VERSION 5.7 ;
BUSBITCHARS "[]" ;
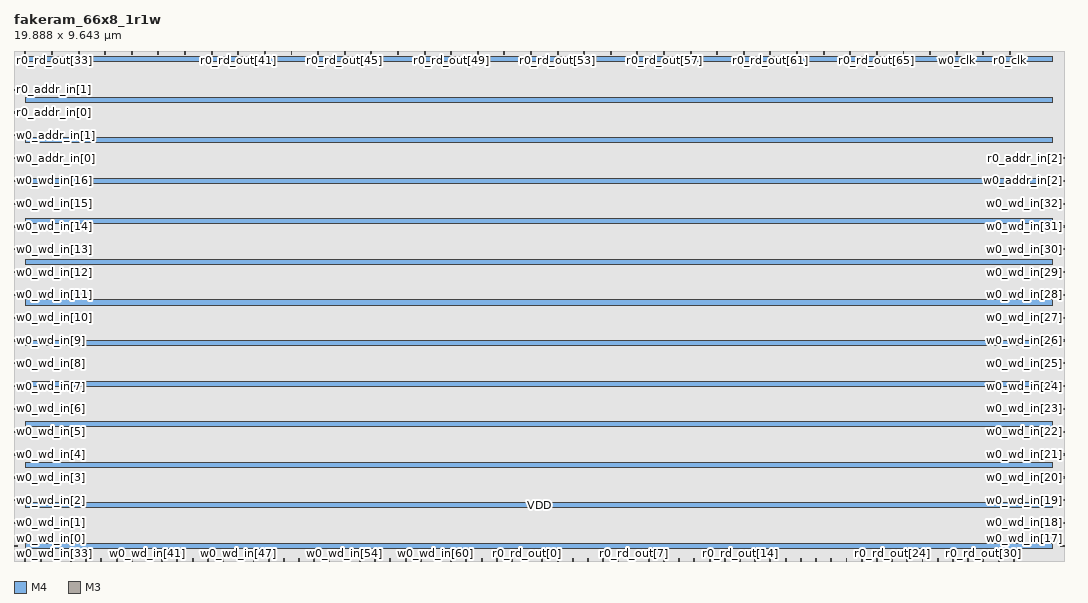
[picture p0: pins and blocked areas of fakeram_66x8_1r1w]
MACRO fakeram_66x8_1r1w
  FOREIGN fakeram_66x8_1r1w 0 0 ;
  SYMMETRY X Y R90 ;
  SIZE 19.888 BY 9.643 ;
  CLASS BLOCK ;
  PIN w0_wd_in[0]
    DIRECTION INPUT ;
    USE SIGNAL ;
    SHAPE ABUTMENT ;
    PORT
      LAYER M4 ;
      RECT 0.000 0.276 0.072 0.300 ;
    END
  END w0_wd_in[0]
  PIN w0_wd_in[1]
    DIRECTION INPUT ;
    USE SIGNAL ;
    SHAPE ABUTMENT ;
    PORT
      LAYER M4 ;
      RECT 0.000 0.708 0.072 0.732 ;
    END
  END w0_wd_in[1]
  PIN w0_wd_in[2]
    DIRECTION INPUT ;
    USE SIGNAL ;
    SHAPE ABUTMENT ;
    PORT
      LAYER M4 ;
      RECT 0.000 1.140 0.072 1.164 ;
    END
  END w0_wd_in[2]
  PIN w0_wd_in[3]
    DIRECTION INPUT ;
    USE SIGNAL ;
    SHAPE ABUTMENT ;
    PORT
      LAYER M4 ;
      RECT 0.000 1.572 0.072 1.596 ;
    END
  END w0_wd_in[3]
  PIN w0_wd_in[4]
    DIRECTION INPUT ;
    USE SIGNAL ;
    SHAPE ABUTMENT ;
    PORT
      LAYER M4 ;
      RECT 0.000 2.004 0.072 2.028 ;
    END
  END w0_wd_in[4]
  PIN w0_wd_in[5]
    DIRECTION INPUT ;
    USE SIGNAL ;
    SHAPE ABUTMENT ;
    PORT
      LAYER M4 ;
      RECT 0.000 2.436 0.072 2.460 ;
    END
  END w0_wd_in[5]
  PIN w0_wd_in[6]
    DIRECTION INPUT ;
    USE SIGNAL ;
    SHAPE ABUTMENT ;
    PORT
      LAYER M4 ;
      RECT 0.000 2.868 0.072 2.892 ;
    END
  END w0_wd_in[6]
  PIN w0_wd_in[7]
    DIRECTION INPUT ;
    USE SIGNAL ;
    SHAPE ABUTMENT ;
    PORT
      LAYER M4 ;
      RECT 0.000 3.300 0.072 3.324 ;
    END
  END w0_wd_in[7]
  PIN w0_wd_in[8]
    DIRECTION INPUT ;
    USE SIGNAL ;
    SHAPE ABUTMENT ;
    PORT
      LAYER M4 ;
      RECT 0.000 3.732 0.072 3.756 ;
    END
  END w0_wd_in[8]
  PIN w0_wd_in[9]
    DIRECTION INPUT ;
    USE SIGNAL ;
    SHAPE ABUTMENT ;
    PORT
      LAYER M4 ;
      RECT 0.000 4.164 0.072 4.188 ;
    END
  END w0_wd_in[9]
  PIN w0_wd_in[10]
    DIRECTION INPUT ;
    USE SIGNAL ;
    SHAPE ABUTMENT ;
    PORT
      LAYER M4 ;
      RECT 0.000 4.596 0.072 4.620 ;
    END
  END w0_wd_in[10]
  PIN w0_wd_in[11]
    DIRECTION INPUT ;
    USE SIGNAL ;
    SHAPE ABUTMENT ;
    PORT
      LAYER M4 ;
      RECT 0.000 5.028 0.072 5.052 ;
    END
  END w0_wd_in[11]
  PIN w0_wd_in[12]
    DIRECTION INPUT ;
    USE SIGNAL ;
    SHAPE ABUTMENT ;
    PORT
      LAYER M4 ;
      RECT 0.000 5.460 0.072 5.484 ;
    END
  END w0_wd_in[12]
  PIN w0_wd_in[13]
    DIRECTION INPUT ;
    USE SIGNAL ;
    SHAPE ABUTMENT ;
    PORT
      LAYER M4 ;
      RECT 0.000 5.892 0.072 5.916 ;
    END
  END w0_wd_in[13]
  PIN w0_wd_in[14]
    DIRECTION INPUT ;
    USE SIGNAL ;
    SHAPE ABUTMENT ;
    PORT
      LAYER M4 ;
      RECT 0.000 6.324 0.072 6.348 ;
    END
  END w0_wd_in[14]
  PIN w0_wd_in[15]
    DIRECTION INPUT ;
    USE SIGNAL ;
    SHAPE ABUTMENT ;
    PORT
      LAYER M4 ;
      RECT 0.000 6.756 0.072 6.780 ;
    END
  END w0_wd_in[15]
  PIN w0_wd_in[16]
    DIRECTION INPUT ;
    USE SIGNAL ;
    SHAPE ABUTMENT ;
    PORT
      LAYER M4 ;
      RECT 0.000 7.188 0.072 7.212 ;
    END
  END w0_wd_in[16]
  PIN w0_wd_in[17]
    DIRECTION INPUT ;
    USE SIGNAL ;
    SHAPE ABUTMENT ;
    PORT
      LAYER M4 ;
      RECT 19.816 0.276 19.888 0.300 ;
    END
  END w0_wd_in[17]
  PIN w0_wd_in[18]
    DIRECTION INPUT ;
    USE SIGNAL ;
    SHAPE ABUTMENT ;
    PORT
      LAYER M4 ;
      RECT 19.816 0.708 19.888 0.732 ;
    END
  END w0_wd_in[18]
  PIN w0_wd_in[19]
    DIRECTION INPUT ;
    USE SIGNAL ;
    SHAPE ABUTMENT ;
    PORT
      LAYER M4 ;
      RECT 19.816 1.140 19.888 1.164 ;
    END
  END w0_wd_in[19]
  PIN w0_wd_in[20]
    DIRECTION INPUT ;
    USE SIGNAL ;
    SHAPE ABUTMENT ;
    PORT
      LAYER M4 ;
      RECT 19.816 1.572 19.888 1.596 ;
    END
  END w0_wd_in[20]
  PIN w0_wd_in[21]
    DIRECTION INPUT ;
    USE SIGNAL ;
    SHAPE ABUTMENT ;
    PORT
      LAYER M4 ;
      RECT 19.816 2.004 19.888 2.028 ;
    END
  END w0_wd_in[21]
  PIN w0_wd_in[22]
    DIRECTION INPUT ;
    USE SIGNAL ;
    SHAPE ABUTMENT ;
    PORT
      LAYER M4 ;
      RECT 19.816 2.436 19.888 2.460 ;
    END
  END w0_wd_in[22]
  PIN w0_wd_in[23]
    DIRECTION INPUT ;
    USE SIGNAL ;
    SHAPE ABUTMENT ;
    PORT
      LAYER M4 ;
      RECT 19.816 2.868 19.888 2.892 ;
    END
  END w0_wd_in[23]
  PIN w0_wd_in[24]
    DIRECTION INPUT ;
    USE SIGNAL ;
    SHAPE ABUTMENT ;
    PORT
      LAYER M4 ;
      RECT 19.816 3.300 19.888 3.324 ;
    END
  END w0_wd_in[24]
  PIN w0_wd_in[25]
    DIRECTION INPUT ;
    USE SIGNAL ;
    SHAPE ABUTMENT ;
    PORT
      LAYER M4 ;
      RECT 19.816 3.732 19.888 3.756 ;
    END
  END w0_wd_in[25]
  PIN w0_wd_in[26]
    DIRECTION INPUT ;
    USE SIGNAL ;
    SHAPE ABUTMENT ;
    PORT
      LAYER M4 ;
      RECT 19.816 4.164 19.888 4.188 ;
    END
  END w0_wd_in[26]
  PIN w0_wd_in[27]
    DIRECTION INPUT ;
    USE SIGNAL ;
    SHAPE ABUTMENT ;
    PORT
      LAYER M4 ;
      RECT 19.816 4.596 19.888 4.620 ;
    END
  END w0_wd_in[27]
  PIN w0_wd_in[28]
    DIRECTION INPUT ;
    USE SIGNAL ;
    SHAPE ABUTMENT ;
    PORT
      LAYER M4 ;
      RECT 19.816 5.028 19.888 5.052 ;
    END
  END w0_wd_in[28]
  PIN w0_wd_in[29]
    DIRECTION INPUT ;
    USE SIGNAL ;
    SHAPE ABUTMENT ;
    PORT
      LAYER M4 ;
      RECT 19.816 5.460 19.888 5.484 ;
    END
  END w0_wd_in[29]
  PIN w0_wd_in[30]
    DIRECTION INPUT ;
    USE SIGNAL ;
    SHAPE ABUTMENT ;
    PORT
      LAYER M4 ;
      RECT 19.816 5.892 19.888 5.916 ;
    END
  END w0_wd_in[30]
  PIN w0_wd_in[31]
    DIRECTION INPUT ;
    USE SIGNAL ;
    SHAPE ABUTMENT ;
    PORT
      LAYER M4 ;
      RECT 19.816 6.324 19.888 6.348 ;
    END
  END w0_wd_in[31]
  PIN w0_wd_in[32]
    DIRECTION INPUT ;
    USE SIGNAL ;
    SHAPE ABUTMENT ;
    PORT
      LAYER M4 ;
      RECT 19.816 6.756 19.888 6.780 ;
    END
  END w0_wd_in[32]
  PIN w0_wd_in[33]
    DIRECTION OUTPUT ;
    USE SIGNAL ;
    SHAPE ABUTMENT ;
    PORT
      LAYER M3 ;
      RECT 0.207 0.000 0.225 0.054 ;
    END
  END w0_wd_in[33]
  PIN w0_wd_in[34]
    DIRECTION OUTPUT ;
    USE SIGNAL ;
    SHAPE ABUTMENT ;
    PORT
      LAYER M3 ;
      RECT 0.495 0.000 0.513 0.054 ;
    END
  END w0_wd_in[34]
  PIN w0_wd_in[35]
    DIRECTION OUTPUT ;
    USE SIGNAL ;
    SHAPE ABUTMENT ;
    PORT
      LAYER M3 ;
      RECT 0.783 0.000 0.801 0.054 ;
    END
  END w0_wd_in[35]
  PIN w0_wd_in[36]
    DIRECTION OUTPUT ;
    USE SIGNAL ;
    SHAPE ABUTMENT ;
    PORT
      LAYER M3 ;
      RECT 1.071 0.000 1.089 0.054 ;
    END
  END w0_wd_in[36]
  PIN w0_wd_in[37]
    DIRECTION OUTPUT ;
    USE SIGNAL ;
    SHAPE ABUTMENT ;
    PORT
      LAYER M3 ;
      RECT 1.359 0.000 1.377 0.054 ;
    END
  END w0_wd_in[37]
  PIN w0_wd_in[38]
    DIRECTION OUTPUT ;
    USE SIGNAL ;
    SHAPE ABUTMENT ;
    PORT
      LAYER M3 ;
      RECT 1.647 0.000 1.665 0.054 ;
    END
  END w0_wd_in[38]
  PIN w0_wd_in[39]
    DIRECTION OUTPUT ;
    USE SIGNAL ;
    SHAPE ABUTMENT ;
    PORT
      LAYER M3 ;
      RECT 1.935 0.000 1.953 0.054 ;
    END
  END w0_wd_in[39]
  PIN w0_wd_in[40]
    DIRECTION OUTPUT ;
    USE SIGNAL ;
    SHAPE ABUTMENT ;
    PORT
      LAYER M3 ;
      RECT 2.223 0.000 2.241 0.054 ;
    END
  END w0_wd_in[40]
  PIN w0_wd_in[41]
    DIRECTION OUTPUT ;
    USE SIGNAL ;
    SHAPE ABUTMENT ;
    PORT
      LAYER M3 ;
      RECT 2.511 0.000 2.529 0.054 ;
    END
  END w0_wd_in[41]
  PIN w0_wd_in[42]
    DIRECTION OUTPUT ;
    USE SIGNAL ;
    SHAPE ABUTMENT ;
    PORT
      LAYER M3 ;
      RECT 2.799 0.000 2.817 0.054 ;
    END
  END w0_wd_in[42]
  PIN w0_wd_in[43]
    DIRECTION OUTPUT ;
    USE SIGNAL ;
    SHAPE ABUTMENT ;
    PORT
      LAYER M3 ;
      RECT 3.087 0.000 3.105 0.054 ;
    END
  END w0_wd_in[43]
  PIN w0_wd_in[44]
    DIRECTION OUTPUT ;
    USE SIGNAL ;
    SHAPE ABUTMENT ;
    PORT
      LAYER M3 ;
      RECT 3.375 0.000 3.393 0.054 ;
    END
  END w0_wd_in[44]
  PIN w0_wd_in[45]
    DIRECTION OUTPUT ;
    USE SIGNAL ;
    SHAPE ABUTMENT ;
    PORT
      LAYER M3 ;
      RECT 3.663 0.000 3.681 0.054 ;
    END
  END w0_wd_in[45]
  PIN w0_wd_in[46]
    DIRECTION OUTPUT ;
    USE SIGNAL ;
    SHAPE ABUTMENT ;
    PORT
      LAYER M3 ;
      RECT 3.951 0.000 3.969 0.054 ;
    END
  END w0_wd_in[46]
  PIN w0_wd_in[47]
    DIRECTION OUTPUT ;
    USE SIGNAL ;
    SHAPE ABUTMENT ;
    PORT
      LAYER M3 ;
      RECT 4.239 0.000 4.257 0.054 ;
    END
  END w0_wd_in[47]
  PIN w0_wd_in[48]
    DIRECTION OUTPUT ;
    USE SIGNAL ;
    SHAPE ABUTMENT ;
    PORT
      LAYER M3 ;
      RECT 4.527 0.000 4.545 0.054 ;
    END
  END w0_wd_in[48]
  PIN w0_wd_in[49]
    DIRECTION OUTPUT ;
    USE SIGNAL ;
    SHAPE ABUTMENT ;
    PORT
      LAYER M3 ;
      RECT 4.815 0.000 4.833 0.054 ;
    END
  END w0_wd_in[49]
  PIN w0_wd_in[50]
    DIRECTION OUTPUT ;
    USE SIGNAL ;
    SHAPE ABUTMENT ;
    PORT
      LAYER M3 ;
      RECT 5.103 0.000 5.121 0.054 ;
    END
  END w0_wd_in[50]
  PIN w0_wd_in[51]
    DIRECTION OUTPUT ;
    USE SIGNAL ;
    SHAPE ABUTMENT ;
    PORT
      LAYER M3 ;
      RECT 5.391 0.000 5.409 0.054 ;
    END
  END w0_wd_in[51]
  PIN w0_wd_in[52]
    DIRECTION OUTPUT ;
    USE SIGNAL ;
    SHAPE ABUTMENT ;
    PORT
      LAYER M3 ;
      RECT 5.679 0.000 5.697 0.054 ;
    END
  END w0_wd_in[52]
  PIN w0_wd_in[53]
    DIRECTION OUTPUT ;
    USE SIGNAL ;
    SHAPE ABUTMENT ;
    PORT
      LAYER M3 ;
      RECT 5.967 0.000 5.985 0.054 ;
    END
  END w0_wd_in[53]
  PIN w0_wd_in[54]
    DIRECTION OUTPUT ;
    USE SIGNAL ;
    SHAPE ABUTMENT ;
    PORT
      LAYER M3 ;
      RECT 6.255 0.000 6.273 0.054 ;
    END
  END w0_wd_in[54]
  PIN w0_wd_in[55]
    DIRECTION OUTPUT ;
    USE SIGNAL ;
    SHAPE ABUTMENT ;
    PORT
      LAYER M3 ;
      RECT 6.543 0.000 6.561 0.054 ;
    END
  END w0_wd_in[55]
  PIN w0_wd_in[56]
    DIRECTION OUTPUT ;
    USE SIGNAL ;
    SHAPE ABUTMENT ;
    PORT
      LAYER M3 ;
      RECT 6.831 0.000 6.849 0.054 ;
    END
  END w0_wd_in[56]
  PIN w0_wd_in[57]
    DIRECTION OUTPUT ;
    USE SIGNAL ;
    SHAPE ABUTMENT ;
    PORT
      LAYER M3 ;
      RECT 7.119 0.000 7.137 0.054 ;
    END
  END w0_wd_in[57]
  PIN w0_wd_in[58]
    DIRECTION OUTPUT ;
    USE SIGNAL ;
    SHAPE ABUTMENT ;
    PORT
      LAYER M3 ;
      RECT 7.407 0.000 7.425 0.054 ;
    END
  END w0_wd_in[58]
  PIN w0_wd_in[59]
    DIRECTION OUTPUT ;
    USE SIGNAL ;
    SHAPE ABUTMENT ;
    PORT
      LAYER M3 ;
      RECT 7.695 0.000 7.713 0.054 ;
    END
  END w0_wd_in[59]
  PIN w0_wd_in[60]
    DIRECTION OUTPUT ;
    USE SIGNAL ;
    SHAPE ABUTMENT ;
    PORT
      LAYER M3 ;
      RECT 7.983 0.000 8.001 0.054 ;
    END
  END w0_wd_in[60]
  PIN w0_wd_in[61]
    DIRECTION OUTPUT ;
    USE SIGNAL ;
    SHAPE ABUTMENT ;
    PORT
      LAYER M3 ;
      RECT 8.271 0.000 8.289 0.054 ;
    END
  END w0_wd_in[61]
  PIN w0_wd_in[62]
    DIRECTION OUTPUT ;
    USE SIGNAL ;
    SHAPE ABUTMENT ;
    PORT
      LAYER M3 ;
      RECT 8.559 0.000 8.577 0.054 ;
    END
  END w0_wd_in[62]
  PIN w0_wd_in[63]
    DIRECTION OUTPUT ;
    USE SIGNAL ;
    SHAPE ABUTMENT ;
    PORT
      LAYER M3 ;
      RECT 8.847 0.000 8.865 0.054 ;
    END
  END w0_wd_in[63]
  PIN w0_wd_in[64]
    DIRECTION OUTPUT ;
    USE SIGNAL ;
    SHAPE ABUTMENT ;
    PORT
      LAYER M3 ;
      RECT 9.135 0.000 9.153 0.054 ;
    END
  END w0_wd_in[64]
  PIN w0_wd_in[65]
    DIRECTION OUTPUT ;
    USE SIGNAL ;
    SHAPE ABUTMENT ;
    PORT
      LAYER M3 ;
      RECT 9.423 0.000 9.441 0.054 ;
    END
  END w0_wd_in[65]
  PIN r0_rd_out[0]
    DIRECTION OUTPUT ;
    USE SIGNAL ;
    SHAPE ABUTMENT ;
    PORT
      LAYER M3 ;
      RECT 9.711 0.000 9.729 0.054 ;
    END
  END r0_rd_out[0]
  PIN r0_rd_out[1]
    DIRECTION OUTPUT ;
    USE SIGNAL ;
    SHAPE ABUTMENT ;
    PORT
      LAYER M3 ;
      RECT 9.999 0.000 10.017 0.054 ;
    END
  END r0_rd_out[1]
  PIN r0_rd_out[2]
    DIRECTION OUTPUT ;
    USE SIGNAL ;
    SHAPE ABUTMENT ;
    PORT
      LAYER M3 ;
      RECT 10.287 0.000 10.305 0.054 ;
    END
  END r0_rd_out[2]
  PIN r0_rd_out[3]
    DIRECTION OUTPUT ;
    USE SIGNAL ;
    SHAPE ABUTMENT ;
    PORT
      LAYER M3 ;
      RECT 10.575 0.000 10.593 0.054 ;
    END
  END r0_rd_out[3]
  PIN r0_rd_out[4]
    DIRECTION OUTPUT ;
    USE SIGNAL ;
    SHAPE ABUTMENT ;
    PORT
      LAYER M3 ;
      RECT 10.863 0.000 10.881 0.054 ;
    END
  END r0_rd_out[4]
  PIN r0_rd_out[5]
    DIRECTION OUTPUT ;
    USE SIGNAL ;
    SHAPE ABUTMENT ;
    PORT
      LAYER M3 ;
      RECT 11.151 0.000 11.169 0.054 ;
    END
  END r0_rd_out[5]
  PIN r0_rd_out[6]
    DIRECTION OUTPUT ;
    USE SIGNAL ;
    SHAPE ABUTMENT ;
    PORT
      LAYER M3 ;
      RECT 11.439 0.000 11.457 0.054 ;
    END
  END r0_rd_out[6]
  PIN r0_rd_out[7]
    DIRECTION OUTPUT ;
    USE SIGNAL ;
    SHAPE ABUTMENT ;
    PORT
      LAYER M3 ;
      RECT 11.727 0.000 11.745 0.054 ;
    END
  END r0_rd_out[7]
  PIN r0_rd_out[8]
    DIRECTION OUTPUT ;
    USE SIGNAL ;
    SHAPE ABUTMENT ;
    PORT
      LAYER M3 ;
      RECT 12.015 0.000 12.033 0.054 ;
    END
  END r0_rd_out[8]
  PIN r0_rd_out[9]
    DIRECTION OUTPUT ;
    USE SIGNAL ;
    SHAPE ABUTMENT ;
    PORT
      LAYER M3 ;
      RECT 12.303 0.000 12.321 0.054 ;
    END
  END r0_rd_out[9]
  PIN r0_rd_out[10]
    DIRECTION OUTPUT ;
    USE SIGNAL ;
    SHAPE ABUTMENT ;
    PORT
      LAYER M3 ;
      RECT 12.591 0.000 12.609 0.054 ;
    END
  END r0_rd_out[10]
  PIN r0_rd_out[11]
    DIRECTION OUTPUT ;
    USE SIGNAL ;
    SHAPE ABUTMENT ;
    PORT
      LAYER M3 ;
      RECT 12.879 0.000 12.897 0.054 ;
    END
  END r0_rd_out[11]
  PIN r0_rd_out[12]
    DIRECTION OUTPUT ;
    USE SIGNAL ;
    SHAPE ABUTMENT ;
    PORT
      LAYER M3 ;
      RECT 13.167 0.000 13.185 0.054 ;
    END
  END r0_rd_out[12]
  PIN r0_rd_out[13]
    DIRECTION OUTPUT ;
    USE SIGNAL ;
    SHAPE ABUTMENT ;
    PORT
      LAYER M3 ;
      RECT 13.455 0.000 13.473 0.054 ;
    END
  END r0_rd_out[13]
  PIN r0_rd_out[14]
    DIRECTION OUTPUT ;
    USE SIGNAL ;
    SHAPE ABUTMENT ;
    PORT
      LAYER M3 ;
      RECT 13.743 0.000 13.761 0.054 ;
    END
  END r0_rd_out[14]
  PIN r0_rd_out[15]
    DIRECTION OUTPUT ;
    USE SIGNAL ;
    SHAPE ABUTMENT ;
    PORT
      LAYER M3 ;
      RECT 14.031 0.000 14.049 0.054 ;
    END
  END r0_rd_out[15]
  PIN r0_rd_out[16]
    DIRECTION OUTPUT ;
    USE SIGNAL ;
    SHAPE ABUTMENT ;
    PORT
      LAYER M3 ;
      RECT 14.319 0.000 14.337 0.054 ;
    END
  END r0_rd_out[16]
  PIN r0_rd_out[17]
    DIRECTION OUTPUT ;
    USE SIGNAL ;
    SHAPE ABUTMENT ;
    PORT
      LAYER M3 ;
      RECT 14.607 0.000 14.625 0.054 ;
    END
  END r0_rd_out[17]
  PIN r0_rd_out[18]
    DIRECTION OUTPUT ;
    USE SIGNAL ;
    SHAPE ABUTMENT ;
    PORT
      LAYER M3 ;
      RECT 14.895 0.000 14.913 0.054 ;
    END
  END r0_rd_out[18]
  PIN r0_rd_out[19]
    DIRECTION OUTPUT ;
    USE SIGNAL ;
    SHAPE ABUTMENT ;
    PORT
      LAYER M3 ;
      RECT 15.183 0.000 15.201 0.054 ;
    END
  END r0_rd_out[19]
  PIN r0_rd_out[20]
    DIRECTION OUTPUT ;
    USE SIGNAL ;
    SHAPE ABUTMENT ;
    PORT
      LAYER M3 ;
      RECT 15.471 0.000 15.489 0.054 ;
    END
  END r0_rd_out[20]
  PIN r0_rd_out[21]
    DIRECTION OUTPUT ;
    USE SIGNAL ;
    SHAPE ABUTMENT ;
    PORT
      LAYER M3 ;
      RECT 15.759 0.000 15.777 0.054 ;
    END
  END r0_rd_out[21]
  PIN r0_rd_out[22]
    DIRECTION OUTPUT ;
    USE SIGNAL ;
    SHAPE ABUTMENT ;
    PORT
      LAYER M3 ;
      RECT 16.047 0.000 16.065 0.054 ;
    END
  END r0_rd_out[22]
  PIN r0_rd_out[23]
    DIRECTION OUTPUT ;
    USE SIGNAL ;
    SHAPE ABUTMENT ;
    PORT
      LAYER M3 ;
      RECT 16.335 0.000 16.353 0.054 ;
    END
  END r0_rd_out[23]
  PIN r0_rd_out[24]
    DIRECTION OUTPUT ;
    USE SIGNAL ;
    SHAPE ABUTMENT ;
    PORT
      LAYER M3 ;
      RECT 16.623 0.000 16.641 0.054 ;
    END
  END r0_rd_out[24]
  PIN r0_rd_out[25]
    DIRECTION OUTPUT ;
    USE SIGNAL ;
    SHAPE ABUTMENT ;
    PORT
      LAYER M3 ;
      RECT 16.911 0.000 16.929 0.054 ;
    END
  END r0_rd_out[25]
  PIN r0_rd_out[26]
    DIRECTION OUTPUT ;
    USE SIGNAL ;
    SHAPE ABUTMENT ;
    PORT
      LAYER M3 ;
      RECT 17.199 0.000 17.217 0.054 ;
    END
  END r0_rd_out[26]
  PIN r0_rd_out[27]
    DIRECTION OUTPUT ;
    USE SIGNAL ;
    SHAPE ABUTMENT ;
    PORT
      LAYER M3 ;
      RECT 17.487 0.000 17.505 0.054 ;
    END
  END r0_rd_out[27]
  PIN r0_rd_out[28]
    DIRECTION OUTPUT ;
    USE SIGNAL ;
    SHAPE ABUTMENT ;
    PORT
      LAYER M3 ;
      RECT 17.775 0.000 17.793 0.054 ;
    END
  END r0_rd_out[28]
  PIN r0_rd_out[29]
    DIRECTION OUTPUT ;
    USE SIGNAL ;
    SHAPE ABUTMENT ;
    PORT
      LAYER M3 ;
      RECT 18.063 0.000 18.081 0.054 ;
    END
  END r0_rd_out[29]
  PIN r0_rd_out[30]
    DIRECTION OUTPUT ;
    USE SIGNAL ;
    SHAPE ABUTMENT ;
    PORT
      LAYER M3 ;
      RECT 18.351 0.000 18.369 0.054 ;
    END
  END r0_rd_out[30]
  PIN r0_rd_out[31]
    DIRECTION OUTPUT ;
    USE SIGNAL ;
    SHAPE ABUTMENT ;
    PORT
      LAYER M3 ;
      RECT 18.639 0.000 18.657 0.054 ;
    END
  END r0_rd_out[31]
  PIN r0_rd_out[32]
    DIRECTION OUTPUT ;
    USE SIGNAL ;
    SHAPE ABUTMENT ;
    PORT
      LAYER M3 ;
      RECT 18.927 0.000 18.945 0.054 ;
    END
  END r0_rd_out[32]
  PIN r0_rd_out[33]
    DIRECTION OUTPUT ;
    USE SIGNAL ;
    SHAPE ABUTMENT ;
    PORT
      LAYER M3 ;
      RECT 0.207 9.589 0.225 9.643 ;
    END
  END r0_rd_out[33]
  PIN r0_rd_out[34]
    DIRECTION OUTPUT ;
    USE SIGNAL ;
    SHAPE ABUTMENT ;
    PORT
      LAYER M3 ;
      RECT 0.711 9.589 0.729 9.643 ;
    END
  END r0_rd_out[34]
  PIN r0_rd_out[35]
    DIRECTION OUTPUT ;
    USE SIGNAL ;
    SHAPE ABUTMENT ;
    PORT
      LAYER M3 ;
      RECT 1.215 9.589 1.233 9.643 ;
    END
  END r0_rd_out[35]
  PIN r0_rd_out[36]
    DIRECTION OUTPUT ;
    USE SIGNAL ;
    SHAPE ABUTMENT ;
    PORT
      LAYER M3 ;
      RECT 1.719 9.589 1.737 9.643 ;
    END
  END r0_rd_out[36]
  PIN r0_rd_out[37]
    DIRECTION OUTPUT ;
    USE SIGNAL ;
    SHAPE ABUTMENT ;
    PORT
      LAYER M3 ;
      RECT 2.223 9.589 2.241 9.643 ;
    END
  END r0_rd_out[37]
  PIN r0_rd_out[38]
    DIRECTION OUTPUT ;
    USE SIGNAL ;
    SHAPE ABUTMENT ;
    PORT
      LAYER M3 ;
      RECT 2.727 9.589 2.745 9.643 ;
    END
  END r0_rd_out[38]
  PIN r0_rd_out[39]
    DIRECTION OUTPUT ;
    USE SIGNAL ;
    SHAPE ABUTMENT ;
    PORT
      LAYER M3 ;
      RECT 3.231 9.589 3.249 9.643 ;
    END
  END r0_rd_out[39]
  PIN r0_rd_out[40]
    DIRECTION OUTPUT ;
    USE SIGNAL ;
    SHAPE ABUTMENT ;
    PORT
      LAYER M3 ;
      RECT 3.735 9.589 3.753 9.643 ;
    END
  END r0_rd_out[40]
  PIN r0_rd_out[41]
    DIRECTION OUTPUT ;
    USE SIGNAL ;
    SHAPE ABUTMENT ;
    PORT
      LAYER M3 ;
      RECT 4.239 9.589 4.257 9.643 ;
    END
  END r0_rd_out[41]
  PIN r0_rd_out[42]
    DIRECTION OUTPUT ;
    USE SIGNAL ;
    SHAPE ABUTMENT ;
    PORT
      LAYER M3 ;
      RECT 4.743 9.589 4.761 9.643 ;
    END
  END r0_rd_out[42]
  PIN r0_rd_out[43]
    DIRECTION OUTPUT ;
    USE SIGNAL ;
    SHAPE ABUTMENT ;
    PORT
      LAYER M3 ;
      RECT 5.247 9.589 5.265 9.643 ;
    END
  END r0_rd_out[43]
  PIN r0_rd_out[44]
    DIRECTION OUTPUT ;
    USE SIGNAL ;
    SHAPE ABUTMENT ;
    PORT
      LAYER M3 ;
      RECT 5.751 9.589 5.769 9.643 ;
    END
  END r0_rd_out[44]
  PIN r0_rd_out[45]
    DIRECTION OUTPUT ;
    USE SIGNAL ;
    SHAPE ABUTMENT ;
    PORT
      LAYER M3 ;
      RECT 6.255 9.589 6.273 9.643 ;
    END
  END r0_rd_out[45]
  PIN r0_rd_out[46]
    DIRECTION OUTPUT ;
    USE SIGNAL ;
    SHAPE ABUTMENT ;
    PORT
      LAYER M3 ;
      RECT 6.759 9.589 6.777 9.643 ;
    END
  END r0_rd_out[46]
  PIN r0_rd_out[47]
    DIRECTION OUTPUT ;
    USE SIGNAL ;
    SHAPE ABUTMENT ;
    PORT
      LAYER M3 ;
      RECT 7.263 9.589 7.281 9.643 ;
    END
  END r0_rd_out[47]
  PIN r0_rd_out[48]
    DIRECTION OUTPUT ;
    USE SIGNAL ;
    SHAPE ABUTMENT ;
    PORT
      LAYER M3 ;
      RECT 7.767 9.589 7.785 9.643 ;
    END
  END r0_rd_out[48]
  PIN r0_rd_out[49]
    DIRECTION OUTPUT ;
    USE SIGNAL ;
    SHAPE ABUTMENT ;
    PORT
      LAYER M3 ;
      RECT 8.271 9.589 8.289 9.643 ;
    END
  END r0_rd_out[49]
  PIN r0_rd_out[50]
    DIRECTION OUTPUT ;
    USE SIGNAL ;
    SHAPE ABUTMENT ;
    PORT
      LAYER M3 ;
      RECT 8.775 9.589 8.793 9.643 ;
    END
  END r0_rd_out[50]
  PIN r0_rd_out[51]
    DIRECTION OUTPUT ;
    USE SIGNAL ;
    SHAPE ABUTMENT ;
    PORT
      LAYER M3 ;
      RECT 9.279 9.589 9.297 9.643 ;
    END
  END r0_rd_out[51]
  PIN r0_rd_out[52]
    DIRECTION OUTPUT ;
    USE SIGNAL ;
    SHAPE ABUTMENT ;
    PORT
      LAYER M3 ;
      RECT 9.783 9.589 9.801 9.643 ;
    END
  END r0_rd_out[52]
  PIN r0_rd_out[53]
    DIRECTION OUTPUT ;
    USE SIGNAL ;
    SHAPE ABUTMENT ;
    PORT
      LAYER M3 ;
      RECT 10.287 9.589 10.305 9.643 ;
    END
  END r0_rd_out[53]
  PIN r0_rd_out[54]
    DIRECTION OUTPUT ;
    USE SIGNAL ;
    SHAPE ABUTMENT ;
    PORT
      LAYER M3 ;
      RECT 10.791 9.589 10.809 9.643 ;
    END
  END r0_rd_out[54]
  PIN r0_rd_out[55]
    DIRECTION OUTPUT ;
    USE SIGNAL ;
    SHAPE ABUTMENT ;
    PORT
      LAYER M3 ;
      RECT 11.295 9.589 11.313 9.643 ;
    END
  END r0_rd_out[55]
  PIN r0_rd_out[56]
    DIRECTION OUTPUT ;
    USE SIGNAL ;
    SHAPE ABUTMENT ;
    PORT
      LAYER M3 ;
      RECT 11.799 9.589 11.817 9.643 ;
    END
  END r0_rd_out[56]
  PIN r0_rd_out[57]
    DIRECTION OUTPUT ;
    USE SIGNAL ;
    SHAPE ABUTMENT ;
    PORT
      LAYER M3 ;
      RECT 12.303 9.589 12.321 9.643 ;
    END
  END r0_rd_out[57]
  PIN r0_rd_out[58]
    DIRECTION OUTPUT ;
    USE SIGNAL ;
    SHAPE ABUTMENT ;
    PORT
      LAYER M3 ;
      RECT 12.807 9.589 12.825 9.643 ;
    END
  END r0_rd_out[58]
  PIN r0_rd_out[59]
    DIRECTION OUTPUT ;
    USE SIGNAL ;
    SHAPE ABUTMENT ;
    PORT
      LAYER M3 ;
      RECT 13.311 9.589 13.329 9.643 ;
    END
  END r0_rd_out[59]
  PIN r0_rd_out[60]
    DIRECTION OUTPUT ;
    USE SIGNAL ;
    SHAPE ABUTMENT ;
    PORT
      LAYER M3 ;
      RECT 13.815 9.589 13.833 9.643 ;
    END
  END r0_rd_out[60]
  PIN r0_rd_out[61]
    DIRECTION OUTPUT ;
    USE SIGNAL ;
    SHAPE ABUTMENT ;
    PORT
      LAYER M3 ;
      RECT 14.319 9.589 14.337 9.643 ;
    END
  END r0_rd_out[61]
  PIN r0_rd_out[62]
    DIRECTION OUTPUT ;
    USE SIGNAL ;
    SHAPE ABUTMENT ;
    PORT
      LAYER M3 ;
      RECT 14.823 9.589 14.841 9.643 ;
    END
  END r0_rd_out[62]
  PIN r0_rd_out[63]
    DIRECTION OUTPUT ;
    USE SIGNAL ;
    SHAPE ABUTMENT ;
    PORT
      LAYER M3 ;
      RECT 15.327 9.589 15.345 9.643 ;
    END
  END r0_rd_out[63]
  PIN r0_rd_out[64]
    DIRECTION OUTPUT ;
    USE SIGNAL ;
    SHAPE ABUTMENT ;
    PORT
      LAYER M3 ;
      RECT 15.831 9.589 15.849 9.643 ;
    END
  END r0_rd_out[64]
  PIN r0_rd_out[65]
    DIRECTION OUTPUT ;
    USE SIGNAL ;
    SHAPE ABUTMENT ;
    PORT
      LAYER M3 ;
      RECT 16.335 9.589 16.353 9.643 ;
    END
  END r0_rd_out[65]
  PIN w0_addr_in[0]
    DIRECTION INPUT ;
    USE SIGNAL ;
    SHAPE ABUTMENT ;
    PORT
      LAYER M4 ;
      RECT 0.000 7.620 0.072 7.644 ;
    END
  END w0_addr_in[0]
  PIN w0_addr_in[1]
    DIRECTION INPUT ;
    USE SIGNAL ;
    SHAPE ABUTMENT ;
    PORT
      LAYER M4 ;
      RECT 0.000 8.052 0.072 8.076 ;
    END
  END w0_addr_in[1]
  PIN w0_addr_in[2]
    DIRECTION INPUT ;
    USE SIGNAL ;
    SHAPE ABUTMENT ;
    PORT
      LAYER M4 ;
      RECT 19.816 7.188 19.888 7.212 ;
    END
  END w0_addr_in[2]
  PIN r0_addr_in[0]
    DIRECTION INPUT ;
    USE SIGNAL ;
    SHAPE ABUTMENT ;
    PORT
      LAYER M4 ;
      RECT 0.000 8.484 0.072 8.508 ;
    END
  END r0_addr_in[0]
  PIN r0_addr_in[1]
    DIRECTION INPUT ;
    USE SIGNAL ;
    SHAPE ABUTMENT ;
    PORT
      LAYER M4 ;
      RECT 0.000 8.916 0.072 8.940 ;
    END
  END r0_addr_in[1]
  PIN r0_addr_in[2]
    DIRECTION INPUT ;
    USE SIGNAL ;
    SHAPE ABUTMENT ;
    PORT
      LAYER M4 ;
      RECT 19.816 7.620 19.888 7.644 ;
    END
  END r0_addr_in[2]
  PIN w0_we_in
    DIRECTION INPUT ;
    USE SIGNAL ;
    SHAPE ABUTMENT ;
    PORT
      LAYER M3 ;
      RECT 16.839 9.589 16.857 9.643 ;
    END
  END w0_we_in
  PIN w0_ce_in
    DIRECTION INPUT ;
    USE SIGNAL ;
    SHAPE ABUTMENT ;
    PORT
      LAYER M3 ;
      RECT 17.343 9.589 17.361 9.643 ;
    END
  END w0_ce_in
  PIN w0_clk
    DIRECTION INPUT ;
    USE SIGNAL ;
    SHAPE ABUTMENT ;
    PORT
      LAYER M3 ;
      RECT 17.847 9.589 17.865 9.643 ;
    END
  END w0_clk
  PIN r0_ce_in
    DIRECTION INPUT ;
    USE SIGNAL ;
    SHAPE ABUTMENT ;
    PORT
      LAYER M3 ;
      RECT 18.351 9.589 18.369 9.643 ;
    END
  END r0_ce_in
  PIN r0_clk
    DIRECTION INPUT ;
    USE SIGNAL ;
    SHAPE ABUTMENT ;
    PORT
      LAYER M3 ;
      RECT 18.855 9.589 18.873 9.643 ;
    END
  END r0_clk
  PIN VSS
    DIRECTION INOUT ;
    USE GROUND ;
    PORT
      LAYER M4 ;
      RECT 0.216 0.240 19.672 0.336 ;
      RECT 0.216 1.008 19.672 1.104 ;
      RECT 0.216 1.776 19.672 1.872 ;
      RECT 0.216 2.544 19.672 2.640 ;
      RECT 0.216 3.312 19.672 3.408 ;
      RECT 0.216 4.080 19.672 4.176 ;
      RECT 0.216 4.848 19.672 4.944 ;
      RECT 0.216 5.616 19.672 5.712 ;
      RECT 0.216 6.384 19.672 6.480 ;
      RECT 0.216 7.152 19.672 7.248 ;
      RECT 0.216 7.920 19.672 8.016 ;
      RECT 0.216 8.688 19.672 8.784 ;
      RECT 0.216 9.456 19.672 9.552 ;
    END
  END VSS
  PIN VDD
    DIRECTION INOUT ;
    USE POWER ;
    PORT
      LAYER M4 ;
      RECT 0.216 0.240 19.672 0.336 ;
      RECT 0.216 1.008 19.672 1.104 ;
      RECT 0.216 1.776 19.672 1.872 ;
      RECT 0.216 2.544 19.672 2.640 ;
      RECT 0.216 3.312 19.672 3.408 ;
      RECT 0.216 4.080 19.672 4.176 ;
      RECT 0.216 4.848 19.672 4.944 ;
      RECT 0.216 5.616 19.672 5.712 ;
      RECT 0.216 6.384 19.672 6.480 ;
      RECT 0.216 7.152 19.672 7.248 ;
      RECT 0.216 7.920 19.672 8.016 ;
      RECT 0.216 8.688 19.672 8.784 ;
      RECT 0.216 9.456 19.672 9.552 ;
    END
  END VDD
  OBS
    LAYER M1 ;
    RECT 0 0 19.888 9.643 ;
    LAYER M2 ;
    RECT 0 0 19.888 9.643 ;
    LAYER M3 ;
    RECT 0 0 19.888 9.643 ;
    LAYER M4 ;
    RECT 0 0 19.888 9.643 ;
  END
END fakeram_66x8_1r1w

END LIBRARY
